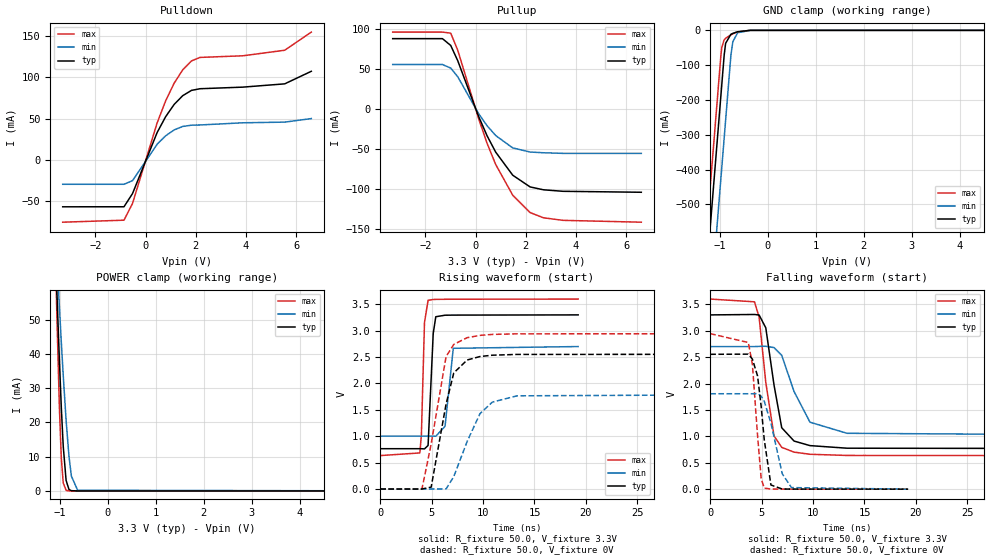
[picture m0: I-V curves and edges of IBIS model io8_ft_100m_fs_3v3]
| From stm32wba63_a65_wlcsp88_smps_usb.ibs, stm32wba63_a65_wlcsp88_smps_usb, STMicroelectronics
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[Model]   io8_ft_100m_fs_3v3
Model_type I/O
Polarity   Non-Inverting
Enable   Active-Low
| CAP_THRESHOLD on pad IOFT is "UDTCAPC" :
| Rising=30.0% of vddiom   Falling=70.0% of vddiom
| C_comp min and max val. don't necessarily correlate with the min and max pvt
| but are the smallest and greatest pad capacitance found.
| var   typ   min   max
C_comp   3.79770pF  3.69235pF  3.85115pF
|C_comp_pullup   2.35214pF  2.17429pF  2.43333pF
|C_comp_pulldown   1.44556pF  1.51806pF  1.41783pF
Vinl = 1.35V
Vinh = 1.8V
Vmeas = 1.65V   | Reference voltage for timing measurements
Cref  = 50.0pF   | Timing specification test load capacitance value
Rref  = 1.0MOhm   | Timing specification test load resistance value
Vref  = 1.815V   | Timing specification test load voltage
[Model Spec]
| TIME_THRESHOLD on pin ZIV11 is "CMOS" :
| Rising=50.0% of vdd   Falling=50.0% of vdd
Vinl 1.29050V 1.08050V 1.37650V
Vinh 1.79850V 1.52050V 1.90250V
| variable   typ   min   max
[Temperature Range] 25.0 140.0 -40.0
| variable   typ   min   max
[Voltage Range] 3.3V 2.7V 3.6V
| variable   typ   min   max
[POWER Clamp Reference] 3.3V 2.7V 3.6V
| variable   typ   min   max
[GND Clamp Reference] 0V 0V 0V
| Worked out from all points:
|   slope of the pulldown table from 0 to 0.495 V, typ, clamps not added: 14 ohm
|   slope of the pullup table from 0 to 0.495 V, typ, clamps not added: 13.8 ohm
|   GND clamp passes 1 mA (typ) near -0.51 V on its own axis
|   POWER clamp passes 1 mA (typ) near -0.83 V on its own axis
|   rising waveform, R_fixture 50.0, V_fixture 3.3V: 20-80 % time 250ps typ, 341ps min, 242ps max; typ from 0.764 V to 3.3 V
|   falling waveform, R_fixture 50.0, V_fixture 3.3V: 20-80 % time 1.12ns typ, 1.99ns min, 1.08ns max; typ from 3.3 V to 0.764 V
|   rising waveform, R_fixture 50.0, V_fixture 0V: 20-80 % time 1.41ns typ, 2.4ns min, 1.46ns max; typ from 0 V to 2.55 V
|   falling waveform, R_fixture 50.0, V_fixture 0V: 20-80 % time 784ps typ, 1.24ns min, 661ps max; typ from 2.55 V to 0 V
[POWER Clamp]
-3.3V     1.123A     753mA      1.645A
-1.09V    69.42mA    75.17mA    67.14mA
-1.08V    65.31mA    72.42mA    61.23mA
-1.06V    57.23mA    66.98mA    49.77mA
-1.01V    38.06mA    53.68mA    24.29mA
-970mV    24.36mA    43.46mA    9.575mA
-930mV    13.06mA    33.74mA    2.352mA
-870mV    3.065mA    20.56mA    165.9uA
-810mV    418.4uA    10.06mA    10.3uA
-760mV    69.41uA    4.321mA    1.009uA
-630mV    611.5nA    197uA      2.727nA
6.6V      0A         0A         0A
[GND Clamp]
-3.3V     -4.134A    -4.372A    -4.018A
-1.59V    -1.227A    -1.465A    -1.111A
-1.25V    -648.9mA   -886.9mA   -533mA
-980mV    -189.9mA   -427.9mA   -74mA
-960mV    -155.9mA   -393.9mA   -48.8mA
-910mV    -70.86mA   -308.9mA   -27.2mA
-880mV    -37.23mA   -257.9mA   -22.76mA
-770mV    -11.28mA   -71.59mA   -12.95mA
-730mV    -8.709mA   -32.74mA   -10.07mA
-630mV    -4.122mA   -6.943mA   -4.354mA
-370mV    -42.68uA   -212.2uA   -13.03uA
6.6V      2.311nA    506.4nA    1.057nA
| variable   typ   min   max
[Pullup Reference] 3.3V 2.7V 3.6V
| variable   typ   min   max
[Pulldown Reference] 0V 0V 0V
[Pullup]
-3.3V     87.39mA    55.15mA    95.56mA
-1.32V    87.39mA    55.15mA    95.56mA
-990mV    78.89mA    50.68mA    94.2mA
-710mV    59.88mA    39.92mA    72.92mA
120mV     -9.566mA   -6.09mA    -12.19mA
460mV     -33.83mA   -21.24mA   -43.26mA
800mV     -54.04mA   -33.36mA   -69.41mA
1.48V     -82.86mA   -48.82mA   -107.8mA
2.17V     -97.42mA   -53.93mA   -129.4mA
2.7V      -101mA     -54.85mA   -135.9mA
3.48V     -102.9mA   -55.62mA   -139.1mA
6.6V      -104.1mA   -55.62mA   -141.4mA
[Pulldown]
-3.3V     -56.7mA    -29.42mA   -75.36mA
-860mV    -56.67mA   -29.42mA   -72.94mA
-520mV    -40.69mA   -25.01mA   -52.64mA
460mV     33.25mA    19.09mA    44.92mA
800mV     52.54mA    29.36mA    71.75mA
1.14V     67.41mA    36.49mA    93.2mA
1.48V     77.97mA    40.67mA    109.3mA
1.83V     84.38mA    42.18mA    120.1mA
2.17V     86.37mA    42.45mA    124.3mA
3.88V     88.31mA    45.1mA     126.3mA
5.54V     92.28mA    45.89mA    133mA
6.6V      107.5mA    50.2mA     155mA
[Ramp]
dV/dt_r 1.53258V/1.41096ns 1.08445V/2.35854ns 1.76673V/1.46232ns
dV/dt_f 1.52157V/1.12301ns 1.019V/1.90102ns 1.77971V/1.07615ns
R_load = 50.0
| Removed startup time: 0s 0s 0s  .
| Removed end time: 19.25ns.
[Rising Waveform]
R_fixture   = 50.0
V_fixture   = 3.3V
V_fixture_min = 2.7V
V_fixture_max = 3.6V
0s        764mV      1.002V     633.8mV
3.85ns    764.1mV    1.002V     683.9mV
4ns       764mV      1.002V     1.032V
4.3ns     759.9mV    1.002V     3.154V
4.65ns    825.9mV    1.002V     3.576V
5.15ns    2.948V     1.002V     3.592V
5.4ns     3.265V     1.001V     3.594V
6.3ns     3.294V     1.188V     3.596V
7.1ns     3.296V     2.667V     3.597V
19.25ns   3.3V       2.7V       3.6V
| Removed startup time: 0s 0s 0s  .
| Removed end time: 59.25ns.
[Falling Waveform]
R_fixture   = 50.0
V_fixture   = 3.3V
V_fixture_min = 2.7V
V_fixture_max = 3.6V
0s        3.3V       2.7V       3.6V
4.3ns     3.308V     2.7V       3.548V
4.75ns    3.298V     2.704V     3.257V
5.4ns     3.055V     2.706V     2.021V
6.2ns     1.973V     2.681V     1.009V
6.95ns    1.163V     2.535V     791.5mV
8.15ns    911.2mV    1.849V     701.3mV
9.7ns     824.8mV    1.268V     660.7mV
13.3ns    775.8mV    1.058V     638.4mV
59.25ns   764mV      1.002V     633.8mV
| Removed startup time: 0s 0s 0s  .
| Removed end time: 59.25ns.
[Rising Waveform]
R_fixture   = 50.0
V_fixture   = 0V
V_fixture_min = 0V
V_fixture_max = 0V
0s        20.8nV     123.7nV    58.33nV
4.05ns    193.8uV    5.146uV    -2.885mV
4.95ns    35.76mV    34.68uV    851.3mV
6.4ns     1.611V     1.837mV    2.511V
7.15ns    2.201V     236.1mV    2.741V
8.45ns    2.445V     901.5mV    2.868V
9.7ns     2.511V     1.429V     2.912V
10.9ns    2.536V     1.647V     2.93V
13.3ns    2.551V     1.766V     2.941V
59.25ns   2.554V     1.807V     2.945V
| Removed startup time: 0s 0s 0s  .
| Removed end time: 19.25ns.
[Falling Waveform]
R_fixture   = 50.0
V_fixture   = 0V
V_fixture_min = 0V
V_fixture_max = 0V
0s        2.554V     1.807V     2.945V
3.7ns     2.557V     1.807V     2.777V
4.1ns     2.462V     1.807V     2.36V
4.6ns     2.143V     1.81V      1.009V
4.95ns    1.567V     1.762V     203.2mV
5.25ns    935.6mV    1.665V     19.13mV
5.9ns     79.06mV    1.25V      2.647mV
7ns       2.54mV     292.4mV    1.373mV
7.9ns     1.543mV    29.8mV     1.011mV
19.25ns   28.21uV    81.63uV    25.08uV
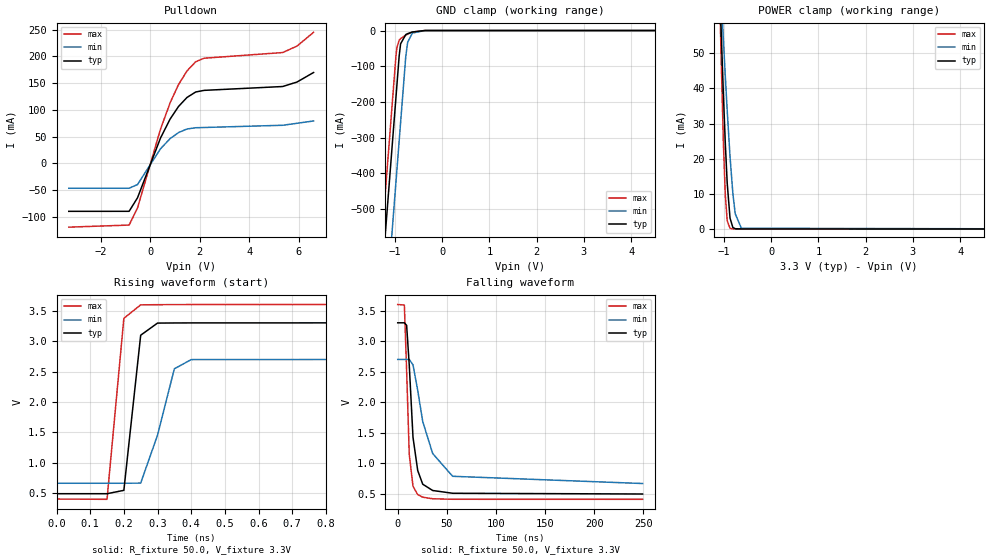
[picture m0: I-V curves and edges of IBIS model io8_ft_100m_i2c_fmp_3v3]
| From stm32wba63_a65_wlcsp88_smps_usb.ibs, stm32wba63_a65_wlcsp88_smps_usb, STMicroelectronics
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[Model]   io8_ft_100m_i2c_fmp_3v3
Model_type I/O_open_drain
Polarity   Non-Inverting
Enable   Active-Low
| CAP_THRESHOLD on pad IOFT is "UDTCAPC" :
| Rising=30.0% of vddiom   Falling=70.0% of vddiom
| C_comp min and max val. don't necessarily correlate with the min and max pvt
| but are the smallest and greatest pad capacitance found.
| var   typ   min   max
C_comp   3.81294pF  3.70667pF  3.87011pF
|C_comp_pulldown   3.81294pF  3.70667pF  3.87011pF
Vinl = 1.35V
Vinh = 1.8V
Vmeas = 1.65V   | Reference voltage for timing measurements
Cref  = 50.0pF   | Timing specification test load capacitance value
Rref  = 1.0MOhm   | Timing specification test load resistance value
Vref  = 1.815V   | Timing specification test load voltage
[Model Spec]
| TIME_THRESHOLD on pin ZII2CV11 is "CMOS" :
| Rising=50.0% of vdd   Falling=50.0% of vdd
Vinl 1.29050V 1.08050V 1.37650V
Vinh 1.79850V 1.52050V 1.90250V
| variable   typ   min   max
[Temperature Range] 25.0 140.0 -40.0
| variable   typ   min   max
[Voltage Range] 3.3V 2.7V 3.6V
| variable   typ   min   max
[POWER Clamp Reference] 3.3V 2.7V 3.6V
| variable   typ   min   max
[GND Clamp Reference] 0V 0V 0V
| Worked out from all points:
|   slope of the pulldown table from 0 to 0.495 V, typ, clamps not added: 8.84 ohm
|   GND clamp passes 1 mA (typ) near -0.51 V on its own axis
|   POWER clamp passes 1 mA (typ) near -0.83 V on its own axis
|   rising waveform, R_fixture 50.0, V_fixture 3.3V: 20-80 % time 33.1ps typ, 62.8ps min, 32.2ps max; typ from 0.496 V to 3.3 V
|   falling waveform, R_fixture 50.0, V_fixture 3.3V: 20-80 % time 7.18ns typ, 18.7ns min, 3.98ns max; typ from 3.3 V to 0.496 V
[POWER Clamp]
-3.3V     1.123A     753mA      1.645A
-1.09V    69.42mA    75.17mA    67.14mA
-1.08V    65.31mA    72.42mA    61.23mA
-1.06V    57.23mA    66.98mA    49.77mA
-1.01V    38.06mA    53.68mA    24.29mA
-970mV    24.36mA    43.46mA    9.575mA
-930mV    13.06mA    33.74mA    2.352mA
-870mV    3.065mA    20.56mA    165.9uA
-810mV    418.4uA    10.06mA    10.3uA
-760mV    69.41uA    4.321mA    1.009uA
-630mV    611.5nA    197uA      2.727nA
6.6V      0A         0A         0A
[GND Clamp]
-3.3V     -4.134A    -4.372A    -4.018A
-1.59V    -1.227A    -1.465A    -1.111A
-1.25V    -648.9mA   -886.9mA   -533mA
-980mV    -189.9mA   -427.9mA   -74mA
-960mV    -155.9mA   -393.9mA   -48.8mA
-910mV    -70.86mA   -308.9mA   -27.2mA
-880mV    -37.23mA   -257.9mA   -22.76mA
-770mV    -11.28mA   -71.59mA   -12.95mA
-730mV    -8.709mA   -32.74mA   -10.07mA
-630mV    -4.122mA   -6.943mA   -4.354mA
-370mV    -42.68uA   -212.2uA   -13.03uA
6.6V      2.311nA    506.4nA    1.057nA
| variable   typ   min   max
[Pullup Reference] 3.3V 2.7V 3.6V
| variable   typ   min   max
[Pulldown Reference] 0V 0V 0V
[Pulldown]
-3.3V     -89.63mA   -46.48mA   -119.2mA
-860mV    -89.58mA   -46.48mA   -115.3mA
-520mV    -64.32mA   -39.52mA   -83.23mA
410mV     47.47mA    27.34mA    64.07mA
800mV     83.04mA    46.39mA    113.5mA
1.14V     106.5mA    57.66mA    147.4mA
1.48V     123.2mA    64.27mA    172.8mA
1.83V     133.4mA    66.65mA    189.9mA
2.17V     136.5mA    67.08mA    196.6mA
5.35V     143.7mA    71.26mA    207.2mA
5.93V     152.1mA    74.98mA    219.3mA
6.6V      169.9mA    79.29mA    245mA
[Ramp]
dV/dt_r 1.6826V/583.11244ps 1.21966V/1.13387ns 1.91502V/366.99636ps
dV/dt_f 1.68262V/7.00601ns 1.21963V/18.44848ns 1.91504V/3.82343ns
R_load = 50.0
| Removed startup time: 0s 0s 0s  .
| Removed end time: 1.7ns.
[Rising Waveform]
R_fixture   = 50.0
V_fixture   = 3.3V
V_fixture_min = 2.7V
V_fixture_max = 3.6V
0s        495.6mV    667.2mV    408.3mV
150ps     495.6mV    667.2mV    403.4mV
200ps     551.1mV    667.2mV    3.373V
250ps     3.096V     669.6mV    3.594V
300ps     3.295V     1.456V     3.597V
350ps     3.297V     2.545V     3.598V
400ps     3.298V     2.696V     3.599V
1.7ns     3.3V       2.7V       3.6V
| Removed startup time: 0s 0s 0s  .
| Removed end time: 249.25ns.
[Falling Waveform]
R_fixture   = 50.0
V_fixture   = 3.3V
V_fixture_min = 2.7V
V_fixture_max = 3.6V
0s        3.3V       2.7V       3.6V
6.75ns    3.3V       2.7V       3.591V
9.05ns    3.259V     2.7V       2.524V
11.75ns   2.606V     2.7V       1.141V
15.55ns   1.425V     2.612V     622.8mV
20.35ns   880.1mV    2.194V     485mV
25.45ns   656.2mV    1.683V     443.2mV
35.6ns    553mV      1.158V     417.6mV
55.95ns   507.6mV    785.6mV    409.3mV
249.3ns   495.6mV    667.3mV    408.3mV
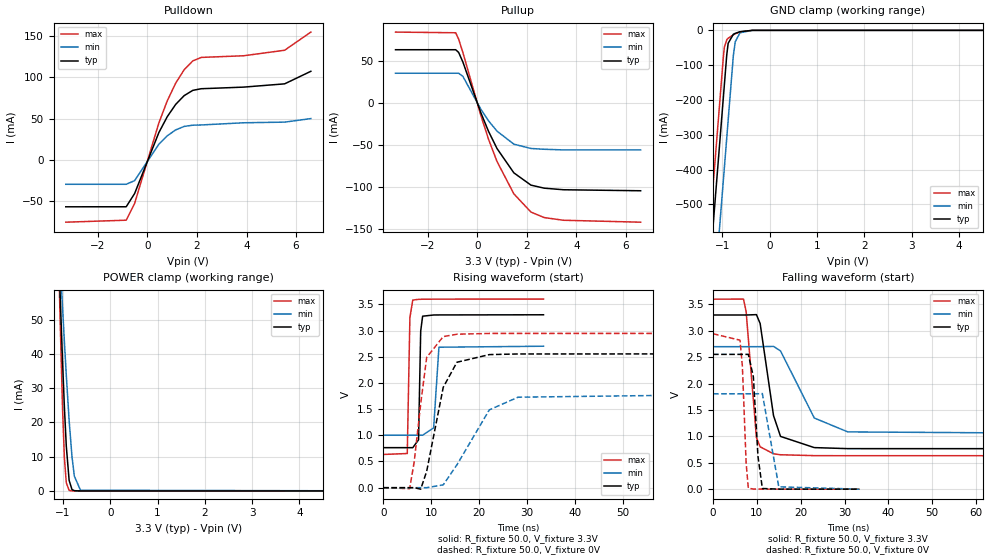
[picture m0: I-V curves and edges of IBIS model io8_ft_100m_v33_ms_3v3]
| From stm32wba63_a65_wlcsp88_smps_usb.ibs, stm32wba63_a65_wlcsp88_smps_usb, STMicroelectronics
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[Model]   io8_ft_100m_v33_ms_3v3
Model_type I/O
Polarity   Non-Inverting
Enable   Active-Low
| CAP_THRESHOLD on pad IOFT is "UDTCAPC" :
| Rising=30.0% of vddiom   Falling=70.0% of vddiom
| C_comp min and max val. don't necessarily correlate with the min and max pvt
| but are the smallest and greatest pad capacitance found.
| var   typ   min   max
C_comp   3.88674pF  3.77801pF  3.94187pF
|C_comp_pullup   2.41867pF  2.25965pF  2.53637pF
|C_comp_pulldown   1.46806pF  1.51835pF  1.40550pF
Vinl = 1.35V
Vinh = 1.8V
Vmeas = 1.65V   | Reference voltage for timing measurements
Cref  = 50.0pF   | Timing specification test load capacitance value
Rref  = 1.0MOhm   | Timing specification test load resistance value
Vref  = 1.815V   | Timing specification test load voltage
[Model Spec]
| TIME_THRESHOLD on pin ZIV33M is "CMOS" :
| Rising=50.0% of vddiom   Falling=50.0% of vddiom
Vinl 1.28450V 1.07450V 1.37050V
Vinh 1.79550V 1.51850V 1.89950V
| variable   typ   min   max
[Temperature Range] 25.0 140.0 -40.0
| variable   typ   min   max
[Voltage Range] 3.3V 2.7V 3.6V
| variable   typ   min   max
[POWER Clamp Reference] 3.3V 2.7V 3.6V
| variable   typ   min   max
[GND Clamp Reference] 0V 0V 0V
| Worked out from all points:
|   slope of the pulldown table from 0 to 0.495 V, typ, clamps not added: 14 ohm
|   slope of the pullup table from 0 to 0.495 V, typ, clamps not added: 13.8 ohm
|   GND clamp passes 1 mA (typ) near -0.51 V on its own axis
|   POWER clamp passes 1 mA (typ) near -0.83 V on its own axis
|   rising waveform, R_fixture 50.0, V_fixture 3.3V: 20-80 % time 264ps typ, 359ps min, 247ps max; typ from 0.764 V to 3.3 V
|   falling waveform, R_fixture 50.0, V_fixture 3.3V: 20-80 % time 2.93ns typ, 6.08ns min, 1.71ns max; typ from 3.3 V to 0.764 V
|   rising waveform, R_fixture 50.0, V_fixture 0V: 20-80 % time 3.4ns typ, 6.88ns min, 2.22ns max; typ from 0 V to 2.55 V
|   falling waveform, R_fixture 50.0, V_fixture 0V: 20-80 % time 1.08ns typ, 1.66ns min, 818ps max; typ from 2.55 V to 0 V
[POWER Clamp]
-3.3V     1.123A     753mA      1.645A
-1.09V    69.42mA    75.17mA    67.14mA
-1.08V    65.31mA    72.42mA    61.23mA
-1.06V    57.23mA    66.98mA    49.77mA
-1.01V    38.06mA    53.68mA    24.29mA
-970mV    24.36mA    43.46mA    9.575mA
-930mV    13.06mA    33.74mA    2.352mA
-870mV    3.065mA    20.56mA    165.9uA
-810mV    418.4uA    10.06mA    10.3uA
-760mV    69.41uA    4.321mA    1.009uA
-630mV    611.5nA    197uA      2.727nA
6.6V      0A         0A         0A
[GND Clamp]
-3.3V     -4.134A    -4.372A    -4.018A
-1.59V    -1.227A    -1.465A    -1.111A
-1.25V    -648.9mA   -886.9mA   -533mA
-980mV    -189.9mA   -427.9mA   -74mA
-960mV    -155.9mA   -393.9mA   -48.8mA
-910mV    -70.86mA   -308.9mA   -27.2mA
-880mV    -37.23mA   -257.9mA   -22.76mA
-770mV    -11.28mA   -71.59mA   -12.95mA
-730mV    -8.709mA   -32.74mA   -10.07mA
-630mV    -4.122mA   -6.943mA   -4.354mA
-370mV    -42.68uA   -212.2uA   -13.03uA
6.6V      2.31nA     506.4nA    1.057nA
| variable   typ   min   max
[Pullup Reference] 3.3V 2.7V 3.6V
| variable   typ   min   max
[Pulldown Reference] 0V 0V 0V
[Pullup]
-3.3V     63.27mA    35.35mA    84.19mA
-870mV    63.27mA    35.35mA    83.39mA
-750mV    60.02mA    35.35mA    75.73mA
-580mV    48.71mA    31.68mA    59.96mA
140mV     -11.11mA   -7.067mA   -14.16mA
460mV     -33.83mA   -21.24mA   -43.26mA
800mV     -54.04mA   -33.36mA   -69.41mA
1.48V     -82.86mA   -48.82mA   -107.8mA
2.17V     -97.42mA   -53.93mA   -129.4mA
2.7V      -101mA     -54.85mA   -135.9mA
3.48V     -102.9mA   -55.62mA   -139.1mA
6.6V      -104.1mA   -55.62mA   -141.4mA
[Pulldown]
-3.3V     -56.7mA    -29.42mA   -75.36mA
-860mV    -56.67mA   -29.42mA   -72.94mA
-520mV    -40.69mA   -25.01mA   -52.64mA
460mV     33.25mA    19.09mA    44.92mA
800mV     52.54mA    29.36mA    71.75mA
1.14V     67.41mA    36.49mA    93.2mA
1.48V     77.97mA    40.67mA    109.3mA
1.83V     84.38mA    42.18mA    120.1mA
2.17V     86.37mA    42.45mA    124.3mA
3.88V     88.31mA    45.11mA    126.3mA
5.54V     92.28mA    45.89mA    133mA
6.6V      107.5mA    50.2mA     155mA
[Ramp]
dV/dt_r 1.53258V/3.33851ns 1.08444V/6.80774ns 1.76673V/2.21529ns
dV/dt_f 1.52157V/2.69177ns 1.019V/5.93039ns 1.77971V/1.7014ns
R_load = 50.0
| Removed startup time: 0s 0s 0s  .
| Removed end time: 33.4ns.
[Rising Waveform]
R_fixture   = 50.0
V_fixture   = 3.3V
V_fixture_min = 2.7V
V_fixture_max = 3.6V
0s        764mV      1.002V     633.8mV
5ns       764.1mV    1.002V     652.3mV
5.55ns    764.1mV    1.002V     3.248V
6.15ns    764.1mV    1.002V     3.581V
7.35ns    913.4mV    1.002V     3.595V
7.8ns     2.989V     1.002V     3.596V
8.2ns     3.273V     1.002V     3.597V
10.5ns    3.296V     1.142V     3.598V
11.6ns    3.297V     2.681V     3.599V
33.4ns    3.3V       2.7V       3.6V
| Removed startup time: 0s 0s 0s  .
| Removed end time: 188.4ns.
[Falling Waveform]
R_fixture   = 50.0
V_fixture   = 3.3V
V_fixture_min = 2.7V
V_fixture_max = 3.6V
0s        3.3V       2.7V       3.6V
6.95ns    3.3V       2.7V       3.602V
7.55ns    3.3V       2.7V       3.365V
9.9ns     3.307V     2.7V       976.7mV
10.75ns   3.138V     2.7V       803mV
13.8ns    1.393V     2.705V     669.9mV
15.4ns    999.5mV    2.619V     652mV
23.1ns    787.5mV    1.348V     635.1mV
30.75ns   768.1mV    1.085V     634mV
188.4ns   764mV      1.002V     633.8mV
| Removed startup time: 0s 0s 0s  .
| Removed end time: 98.35ns.
[Rising Waveform]
R_fixture   = 50.0
V_fixture   = 0V
V_fixture_min = 0V
V_fixture_max = 0V
0s        20.88nV    123.8nV    58.45nV
5.5ns     2.011uV    120.1nV    -18.83mV
6.45ns    78.41uV    127.1nV    496.8mV
7.8ns     -28.33mV   2.567uV    1.599V
9.05ns    313.5mV    19.61uV    2.488V
12.5ns    1.916V     54.09mV    2.884V
15.35ns   2.394V     435.4mV    2.929V
22.1ns    2.54V      1.485V     2.944V
28.1ns    2.552V     1.727V     2.944V
98.35ns   2.554V     1.807V     2.945V
| Removed startup time: 0s 0s 0s  .
| Removed end time: 33.4ns.
[Falling Waveform]
R_fixture   = 50.0
V_fixture   = 0V
V_fixture_min = 0V
V_fixture_max = 0V
0s        2.554V     1.807V     2.945V
6.15ns    2.554V     1.807V     2.823V
6.7ns     2.554V     1.807V     2.324V
7.55ns    2.554V     1.807V     496mV
8.05ns    2.554V     1.807V     18.68mV
9.2ns     2.13V      1.807V     1.981mV
10.25ns   626.4mV    1.807V     1.228mV
11.25ns   12.65mV    1.812V     921.3uV
15ns      971.6uV    44.15mV    423.8uV
33.4ns    28.91uV    219uV      3.058uV
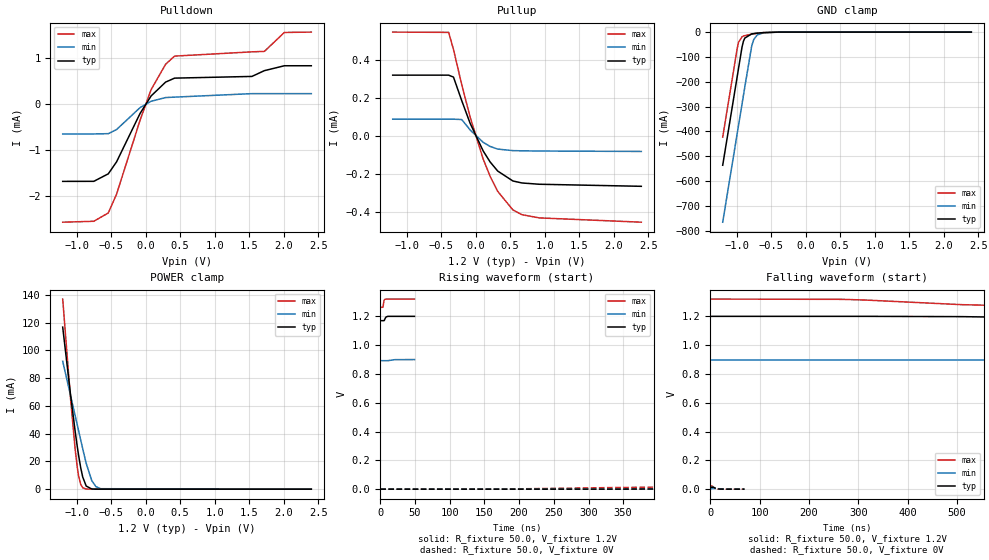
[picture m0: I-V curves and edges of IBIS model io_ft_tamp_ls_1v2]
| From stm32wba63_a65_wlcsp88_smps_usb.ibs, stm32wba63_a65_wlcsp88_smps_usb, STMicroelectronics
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[Model]   io_ft_tamp_ls_1v2
Model_type I/O
Polarity   Non-Inverting
Enable   Active-Low
| CAP_THRESHOLD on pad IOFT is "UDTCAPC" :
| Rising=30.0% of vddios   Falling=70.0% of vddios
| C_comp min and max val. don't necessarily correlate with the min and max pvt
| but are the smallest and greatest pad capacitance found.
| var   typ   min   max
C_comp   2.36572pF  2.32096pF  2.42359pF
|C_comp_pullup   1.37557pF  1.27769pF  1.46043pF
|C_comp_pulldown   990.15399fF  1.04327pF  963.15792fF
Vinl = 450.0mV
Vinh = 660.0mV
Vmeas = 600.0mV   | Reference voltage for timing measurements
Cref  = 50.0pF   | Timing specification test load capacitance value
Rref  = 1.0MOhm   | Timing specification test load resistance value
Vref  = 660.0mV   | Timing specification test load voltage
[Model Spec]
| TIME_THRESHOLD on pin ZIV11 is "CMOS" :
| Rising=50.0% of vdd   Falling=50.0% of vdd
Vinl 441.50000mV 335.50000mV 487.50000mV
Vinh 755.50000mV 552.50000mV 839.50000mV
| variable   typ   min   max
[Temperature Range] 25.0 140.0 -40.0
| variable   typ   min   max
[Voltage Range] 1.2V 900.0mV 1.32V
| variable   typ   min   max
[POWER Clamp Reference] 1.2V 900.0mV 1.32V
| variable   typ   min   max
[GND Clamp Reference] 0V 0V 0V
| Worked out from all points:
|   slope of the pulldown table from 0 to 0.18 V, typ, clamps not added: 522 ohm
|   slope of the pullup table from 0 to 0.18 V, typ, clamps not added: 1.49 kohm
|   GND clamp passes 1 mA (typ) near -0.54 V on its own axis
|   POWER clamp passes 1 mA (typ) near -0.83 V on its own axis
[POWER Clamp]
-1.2V     116.7mA    92.13mA    136.9mA
-1.09V    69.42mA    68.21mA    67.14mA
-1.02V    41.75mA    52.99mA    28.91mA
-990mV    30.98mA    46.47mA    16.09mA
-970mV    24.36mA    42.12mA    9.575mA
-940mV    15.59mA    35.6mA     3.485mA
-910mV    8.693mA    29.07mA    1.01mA
-860mV    2.259mA    18.59mA    104.6uA
-780mV    143.1uA    6.246mA    2.554uA
-720mV    16.22uA    1.846mA    157.1nA
-650mV    1.266uA    330.3uA    6.104nA
2.4V      0A         0A         0A
[GND Clamp]
-1.2V     -535.9mA   -765.1mA   -422.7mA
-990mV    -178.9mA   -408.1mA   -65.72mA
-970mV    -144.9mA   -374.1mA   -40.58mA
-920mV    -59.91mA   -289.1mA   -18.78mA
-900mV    -37.04mA   -255.1mA   -15.98mA
-880mV    -24.11mA   -221.1mA   -14.15mA
-780mV    -7.189mA   -55.54mA   -8.417mA
-750mV    -5.884mA   -29.71mA   -7.031mA
-700mV    -4.228mA   -11.41mA   -4.967mA
-610mV    -2.056mA   -3.105mA   -2.146mA
-390mV    -47.28uA   -188.8uA   -17.26uA
2.4V      740.6pA    197.9nA    245.1pA
| variable   typ   min   max
[Pullup Reference] 1.2V 900.0mV 1.32V
| variable   typ   min   max
[Pulldown Reference] 0V 0V 0V
[Pullup]
-1.2V     321.3uA    88.9uA     548.6uA
-390mV    321.3uA    88.9uA     547.1uA
-320mV    311uA      88.9uA     456.9uA
-200mV    186.3uA    86.88uA    270.6uA
-80mV     68.07uA    32.43uA    101.5uA
110mV     -78.95uA   -33.53uA   -121.5uA
210mV     -136.6uA   -54.89uA   -212.5uA
320mV     -184.8uA   -68.93uA   -292uA
540mV     -237.3uA   -77.06uA   -389.8uA
670mV     -247.8uA   -78.09uA   -415.1uA
920mV     -254.6uA   -79.22uA   -432.2uA
2.4V      -265.5uA   -81.48uA   -454.9uA
[Pulldown]
-1.2V     -1.691mA   -654.4uA   -2.583mA
-750mV    -1.69mA    -654.4uA   -2.563mA
-540mV    -1.526mA   -648uA     -2.381mA
-420mV    -1.264mA   -558.1uA   -1.971mA
-80mV     -206.7uA   -79.07uA   -354.6uA
80mV      176uA      59.8uA     314uA
290mV     478.8uA    141uA      868.7uA
420mV     565.7uA    150.3uA    1.047mA
1.54V     603uA      226.7uA    1.14mA
1.72V     729uA      226.7uA    1.15mA
2.01V     836.2uA    226.7uA    1.564mA
2.4V      836.2uA    226.7uA    1.572mA
[Ramp]
dV/dt_r 7.74089mV/409.16727ns 2.36364mV/1.05135us 13.24767mV/226.86306ns
dV/dt_f 17.9434mV/387.10712ns 4.52375mV/1.02758us 34.19464mV/229.19862ns
R_load = 50.0
| Removed startup time: 0s 0s 0s  .
| Removed end time: 49.25ns.
[Rising Waveform]
R_fixture   = 50.0
V_fixture   = 1.2V
V_fixture_min = 900.0mV
V_fixture_max = 1.32V
0s        1.17V      892.4mV    1.263V
3.85ns    1.17V      892.4mV    1.263V
5.05ns    1.17V      892.4mV    1.3V
5.45ns    1.17V      892.4mV    1.31V
6.15ns    1.175V     892.4mV    1.317V
6.95ns    1.185V     892.4mV    1.319V
8.35ns    1.196V     892.4mV    1.32V
11.05ns   1.2V       892.4mV    1.32V
21.15ns   1.2V       899.3mV    1.32V
49.25ns   1.2V       900mV      1.32V
| Removed startup time: 0s 0s 0s  .
| Removed end time: 4.9989us.
[Falling Waveform]
R_fixture   = 50.0
V_fixture   = 1.2V
V_fixture_min = 900.0mV
V_fixture_max = 1.32V
0s        1.2V       900mV      1.32V
268.9ns   1.2V       900mV      1.318V
315.4ns   1.2V       900mV      1.313V
510.1ns   1.198V     900mV      1.281V
666ns     1.19V      900mV      1.269V
842.6ns   1.181V     900mV      1.264V
1.122us   1.173V     899.9mV    1.263V
1.53us    1.171V     898.8mV    1.263V
2.857us   1.17V      893.5mV    1.263V
4.999us   1.17V      892.5mV    1.263V
| Removed startup time: 0s 0s 0s  .
| Removed end time: 4.9989us.
[Rising Waveform]
R_fixture   = 50.0
V_fixture   = 0V
V_fixture_min = 0V
V_fixture_max = 0V
0s        10.49nV    318.6nV    9.881nV
171ns     -2.032uV   -719.7nV   482.6uV
322.1ns   175.3uV    -449.9nV   10.27mV
449.4ns   2.251mV    125.3nV    17.03mV
584.3ns   5.415mV    2.338uV    20.3mV
714.4ns   8.086mV    8.216uV    21.45mV
1.02us    11.47mV    83.73uV    22.01mV
1.429us   12.65mV    805.2uV    22.07mV
2.755us   12.9mV     3.449mV    22.08mV
4.999us   12.9mV     3.94mV     22.08mV
| Removed startup time: 0s 0s 0s  .
| Removed end time: 69.25ns.
[Falling Waveform]
R_fixture   = 50.0
V_fixture   = 0V
V_fixture_min = 0V
V_fixture_max = 0V
0s        12.91mV    3.958mV    22.08mV
3.95ns    12.9mV     3.958mV    22.13mV
5.95ns    12.88mV    3.957mV    15.52mV
9.8ns     8.016mV    3.963mV    5.097mV
11.95ns   5.669mV    3.944mV    1.652mV
14.5ns    3.331mV    3.487mV    335.6uV
18.4ns    882.3uV    2.825mV    139uV
22.65ns   192.9uV    2.166mV    65.4uV
41ns      18.69uV    289.4uV    2.611uV
69.25ns   923.4nV    22.15uV    1.133uV
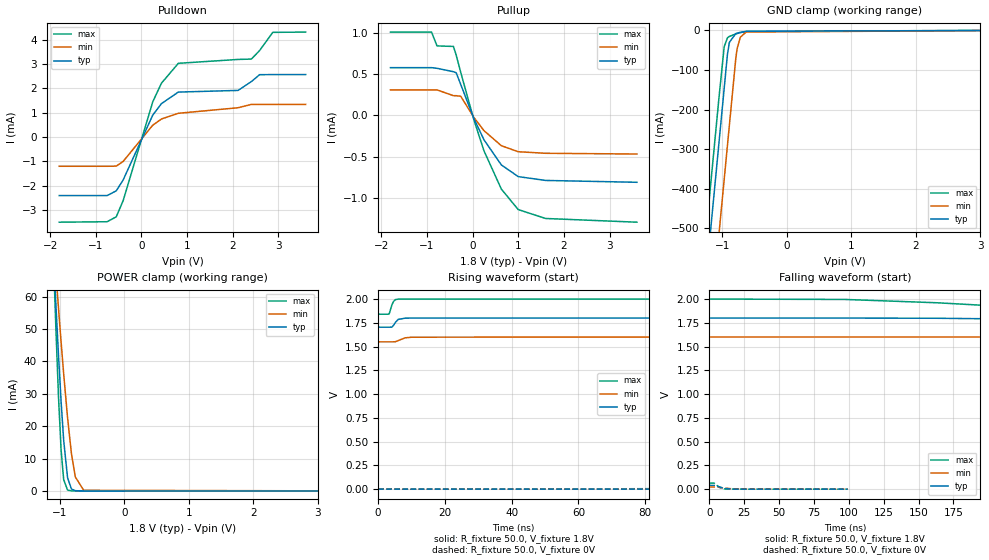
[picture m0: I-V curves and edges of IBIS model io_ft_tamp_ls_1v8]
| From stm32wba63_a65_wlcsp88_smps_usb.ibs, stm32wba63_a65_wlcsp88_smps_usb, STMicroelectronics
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[Model]   io_ft_tamp_ls_1v8
Model_type I/O
Polarity   Non-Inverting
Enable   Active-Low
| CAP_THRESHOLD on pad IOFT is "UDTCAPC" :
| Rising=30.0% of vddios   Falling=70.0% of vddios
| C_comp min and max val. don't necessarily correlate with the min and max pvt
| but are the smallest and greatest pad capacitance found.
| var   typ   min   max
C_comp   2.67029pF  2.66323pF  2.74961pF
|C_comp_pullup   1.57191pF  1.51367pF  1.65630pF
|C_comp_pulldown   1.09837pF  1.14956pF  1.09331pF
Vinl = 800.0mV
Vinh = 1.0V
Vmeas = 900.0mV   | Reference voltage for timing measurements
Cref  = 50.0pF   | Timing specification test load capacitance value
Rref  = 1.0MOhm   | Timing specification test load resistance value
Vref  = 990.0mV   | Timing specification test load voltage
[Model Spec]
| TIME_THRESHOLD on pin ZIV11 is "CMOS" :
| Rising=50.0% of vdd   Falling=50.0% of vdd
Vinl 702.50000mV 626.50000mV 788.50000mV
Vinh 1.09050V 959.50000mV 1.19650V
| variable   typ   min   max
[Temperature Range] 25.0 140.0 -40.0
| variable   typ   min   max
[Voltage Range] 1.8V 1.6V 2.0V
| variable   typ   min   max
[POWER Clamp Reference] 1.8V 1.6V 2.0V
| variable   typ   min   max
[GND Clamp Reference] 0V 0V 0V
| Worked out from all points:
|   slope of the pulldown table from 0 to 0.27 V, typ, clamps not added: 284 ohm
|   slope of the pullup table from 0 to 0.27 V, typ, clamps not added: 860 ohm
|   GND clamp passes 1 mA (typ) near -0.54 V on its own axis
|   POWER clamp passes 1 mA (typ) near -0.83 V on its own axis
|   rising waveform, R_fixture 50.0, V_fixture 1.8V: 20-80 % time 1.22ns typ, NA min, 931ps max; typ from 1.7 V to 1.8 V
|   falling waveform, R_fixture 50.0, V_fixture 1.8V: 20-80 % time 214ns typ, NA min, 141ns max; typ from 1.8 V to 1.7 V
[POWER Clamp]
-1.8V     396.4mA    285.5mA    556.9mA
-1.09V    69.42mA    75.17mA    67.14mA
-1.08V    65.31mA    72.42mA    61.23mA
-1.06V    57.23mA    66.98mA    49.77mA
-1.02V    41.75mA    56.3mA     28.91mA
-980mV    27.6mA     45.97mA    12.6mA
-940mV    15.59mA    36.11mA    3.485mA
-880mV    4.091mA    22.61mA    262.5uA
-820mV    594.6uA    11.56mA    16.39uA
-760mV    69.41uA    4.321mA    1.008uA
-630mV    610.8nA    197uA      2.464nA
3.6V      0A         0A         0A
[GND Clamp]
-1.8V     -1.557A    -1.787A    -1.443A
-1.33V    -757.8mA   -987.8mA   -644.3mA
-1.24V    -604.8mA   -834.8mA   -491.3mA
-1.05V    -281.8mA   -511.8mA   -168.3mA
-970mV    -145.8mA   -375.8mA   -41.09mA
-920mV    -60.82mA   -290.8mA   -19.19mA
-890mV    -30.35mA   -239.8mA   -15.35mA
-790mV    -8.023mA   -70.37mA   -9.131mA
-770mV    -6.967mA   -46.42mA   -8.145mA
-720mV    -5.017mA   -17.37mA   -5.895mA
-630mV    -2.538mA   -4.268mA   -2.717mA
3.6V      1.094nA    260.9nA    370.3pA
| variable   typ   min   max
[Pullup Reference] 1.8V 1.6V 2.0V
| variable   typ   min   max
[Pulldown Reference] 0V 0V 0V
[Pullup]
-1.8V     581uA      310.8uA    1.013mA
-900mV    581uA      310.8uA    1.013mA
-780mV    573uA      310.8uA    845uA
-420mV    531.8uA    240.6uA    838.7uA
-360mV    519.6uA    240.6uA    734.4uA
-260mV    377.1uA    233.1uA    523.7uA
30mV      -39.57uA   -24.87uA   -57.04uA
250mV     -295.5uA   -184.4uA   -429.9uA
630mV     -600.6uA   -367.2uA   -894uA
1V        -742.5uA   -440.3uA   -1.143mA
1.6V      -788.9uA   -459.1uA   -1.251mA
3.6V      -811.3uA   -468uA     -1.296mA
[Pulldown]
-1.8V     -2.401mA   -1.198mA   -3.493mA
-750mV    -2.4mA     -1.198mA   -3.474mA
-550mV    -2.207mA   -1.193mA   -3.271mA
-400mV    -1.763mA   -1.002mA   -2.612mA
250mV     901.5uA    487.8uA    1.448mA
440mV     1.372mA    740.4uA    2.21mA
810mV     1.846mA    975.3uA    3.026mA
2.12V     1.914mA    1.203mA    3.185mA
2.41V     2.276mA    1.339mA    3.199mA
2.59V     2.559mA    1.339mA    3.547mA
2.88V     2.564mA    1.339mA    4.296mA
3.6V      2.564mA    1.339mA    4.307mA
[Ramp]
dV/dt_r 23.80185mV/239.86131ns 13.72602mV/467.94544ns 38.015mV/140.17815ns
dV/dt_f 57.33007mV/213.40371ns 29.79554mV/373.12078ns 95.55754mV/139.49218ns
R_load = 50.0
| Removed startup time: 0s 0s 0s  .
| Removed end time: 99.2ns.
[Rising Waveform]
R_fixture   = 50.0
V_fixture   = 1.8V
V_fixture_min = 1.6V
V_fixture_max = 2.0V
0s        1.704V     1.55V      1.841V
3.2ns     1.704V     1.55V      1.841V
3.4ns     1.704V     1.55V      1.854V
4.15ns    1.705V     1.55V      1.941V
4.6ns     1.724V     1.55V      1.974V
5.15ns    1.753V     1.551V     1.994V
6ns       1.786V     1.563V     1.999V
8.1ns     1.799V     1.592V     2V
10.15ns   1.8V       1.599V     2V
99.2ns    1.8V       1.6V       2V
| Removed startup time: 0s 0s 0s  .
| Removed end time: 1.999us.
[Falling Waveform]
R_fixture   = 50.0
V_fixture   = 1.8V
V_fixture_min = 1.6V
V_fixture_max = 2.0V
0s        1.8V       1.6V       2V
97.25ns   1.8V       1.6V       1.996V
163.3ns   1.798V     1.6V       1.961V
236.3ns   1.787V     1.6V       1.902V
266.5ns   1.779V     1.599V     1.884V
323.8ns   1.76V      1.597V     1.862V
408ns     1.736V     1.593V     1.848V
602ns     1.711V     1.575V     1.841V
935.5ns   1.705V     1.556V     1.841V
1.999us   1.704V     1.55V      1.841V
| Removed startup time: 0s 0s 0s  .
| Removed end time: 1.999us.
[Rising Waveform]
R_fixture   = 50.0
V_fixture   = 0V
V_fixture_min = 0V
V_fixture_max = 0V
0s        14.23nV    329.4nV    13.51nV
48ns      -14.01uV   -6.167uV   257.4uV
81.5ns    87.28uV    -3.874uV   5.35mV
197.3ns   6.914mV    248uV      39.11mV
246.3ns   12.36mV    691.1uV    49.71mV
367.3ns   25.92mV    3.52mV     60.48mV
489.5ns   33.82mV    7.633mV    62.79mV
693.5ns   38.4mV     14.4mV     63.3mV
1.143us   39.62mV    21.31mV    63.35mV
1.999us   39.67mV    22.88mV    63.36mV
| Removed startup time: 0s 0s 0s  .
| Removed end time: 99.2ns.
[Falling Waveform]
R_fixture   = 50.0
V_fixture   = 0V
V_fixture_min = 0V
V_fixture_max = 0V
0s        39.68mV    22.94mV    63.36mV
3.5ns     39.67mV    22.94mV    63.25mV
4.55ns    39.33mV    22.95mV    50.45mV
6.15ns    29.99mV    21.19mV    30.9mV
7.45ns    22.8mV     18.41mV    17.87mV
10.15ns   10.36mV    13.07mV    4.682mV
11.7ns    6.44mV     10.31mV    729.5uV
16.2ns    366.5uV    4.239mV    134.9uV
24.3ns    57.1uV     243uV      12.08uV
99.2ns    2.596uV    1.43uV     7.333uV
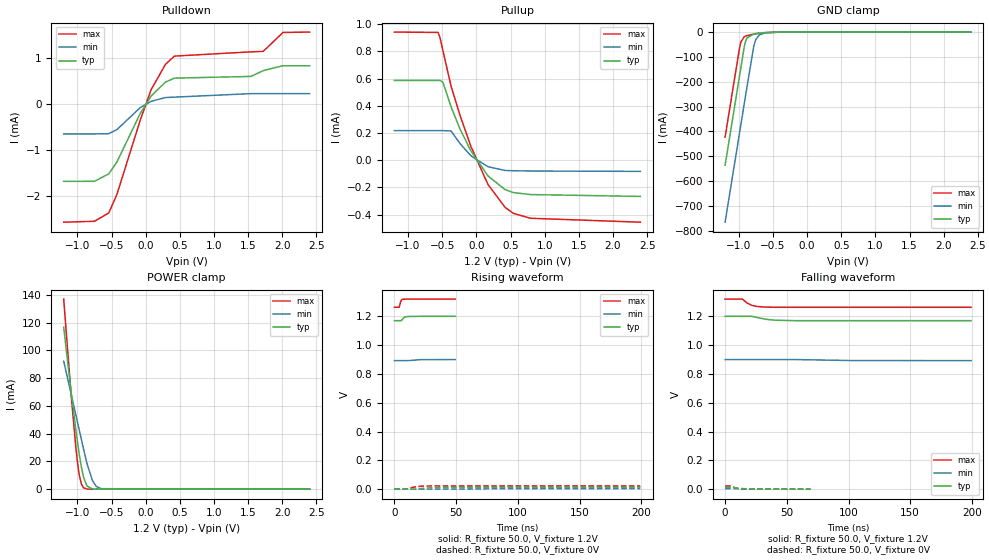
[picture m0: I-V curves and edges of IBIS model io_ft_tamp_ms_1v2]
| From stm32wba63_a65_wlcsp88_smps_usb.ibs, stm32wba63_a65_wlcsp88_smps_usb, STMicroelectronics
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[Model]   io_ft_tamp_ms_1v2
Model_type I/O
Polarity   Non-Inverting
Enable   Active-Low
| CAP_THRESHOLD on pad IOFT is "UDTCAPC" :
| Rising=30.0% of vddios   Falling=70.0% of vddios
| C_comp min and max val. don't necessarily correlate with the min and max pvt
| but are the smallest and greatest pad capacitance found.
| var   typ   min   max
C_comp   2.32868pF  2.27595pF  2.39710pF
|C_comp_pullup   1.36499pF  1.26587pF  1.45240pF
|C_comp_pulldown   963.69029fF  1.01008pF  944.70272fF
Vinl = 450.0mV
Vinh = 660.0mV
Vmeas = 600.0mV   | Reference voltage for timing measurements
Cref  = 50.0pF   | Timing specification test load capacitance value
Rref  = 1.0MOhm   | Timing specification test load resistance value
Vref  = 660.0mV   | Timing specification test load voltage
[Model Spec]
| TIME_THRESHOLD on pin ZIV11 is "CMOS" :
| Rising=50.0% of vdd   Falling=50.0% of vdd
Vinl 441.50000mV 335.50000mV 487.50000mV
Vinh 755.50000mV 552.50000mV 839.50000mV
| variable   typ   min   max
[Temperature Range] 25.0 140.0 -40.0
| variable   typ   min   max
[Voltage Range] 1.2V 900.0mV 1.32V
| variable   typ   min   max
[POWER Clamp Reference] 1.2V 900.0mV 1.32V
| variable   typ   min   max
[GND Clamp Reference] 0V 0V 0V
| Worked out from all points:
|   slope of the pulldown table from 0 to 0.18 V, typ, clamps not added: 522 ohm
|   slope of the pullup table from 0 to 0.18 V, typ, clamps not added: 1.49 kohm
|   GND clamp passes 1 mA (typ) near -0.54 V on its own axis
|   POWER clamp passes 1 mA (typ) near -0.83 V on its own axis
[POWER Clamp]
-1.2V     116.7mA    92.13mA    136.9mA
-1.09V    69.42mA    68.21mA    67.14mA
-1.02V    41.75mA    52.99mA    28.91mA
-990mV    30.98mA    46.47mA    16.09mA
-970mV    24.36mA    42.12mA    9.575mA
-940mV    15.59mA    35.6mA     3.485mA
-910mV    8.693mA    29.07mA    1.01mA
-860mV    2.259mA    18.59mA    104.6uA
-780mV    143.1uA    6.246mA    2.554uA
-720mV    16.22uA    1.846mA    157.1nA
-650mV    1.266uA    330.3uA    6.104nA
2.4V      0A         0A         0A
[GND Clamp]
-1.2V     -535.9mA   -765.1mA   -422.7mA
-990mV    -178.9mA   -408.1mA   -65.72mA
-970mV    -144.9mA   -374.1mA   -40.58mA
-920mV    -59.91mA   -289.1mA   -18.78mA
-900mV    -37.04mA   -255.1mA   -15.98mA
-880mV    -24.11mA   -221.1mA   -14.15mA
-780mV    -7.189mA   -55.54mA   -8.417mA
-750mV    -5.884mA   -29.71mA   -7.031mA
-700mV    -4.228mA   -11.41mA   -4.967mA
-610mV    -2.056mA   -3.105mA   -2.146mA
-390mV    -47.28uA   -188.8uA   -17.26uA
2.4V      740.6pA    197.9nA    245.1pA
| variable   typ   min   max
[Pullup Reference] 1.2V 900.0mV 1.32V
| variable   typ   min   max
[Pulldown Reference] 0V 0V 0V
[Pullup]
-1.2V     586.5uA    218uA      941.8uA
-560mV    586.5uA    218uA      939.3uA
-530mV    586.5uA    218uA      896.2uA
-490mV    573uA      218uA      805.2uA
-370mV    392.1uA    215.1uA    543.5uA
-240mV    230uA      123.4uA    331.1uA
-80mV     68.07uA    32.58uA    101.5uA
170mV     -115.1uA   -47.4uA    -178.3uA
420mV     -215.5uA   -74.74uA   -346.1uA
540mV     -237.3uA   -77.13uA   -389.8uA
790mV     -251.9uA   -78.78uA   -426uA
2.4V      -265.6uA   -81.56uA   -454.9uA
[Pulldown]
-1.2V     -1.691mA   -654.5uA   -2.583mA
-750mV    -1.69mA    -654.5uA   -2.563mA
-540mV    -1.526mA   -648.1uA   -2.381mA
-420mV    -1.264mA   -558.3uA   -1.971mA
-80mV     -206.7uA   -79.1uA    -354.6uA
80mV      176uA      59.82uA    314uA
290mV     478.8uA    141.1uA    868.7uA
420mV     565.7uA    150.4uA    1.047mA
1.54V     603uA      226.8uA    1.14mA
1.72V     729uA      226.8uA    1.15mA
2.01V     836.2uA    226.8uA    1.564mA
2.4V      836.2uA    226.8uA    1.572mA
[Ramp]
dV/dt_r 7.74199mV/11.17719ns 2.37132mV/29.62579ns 13.24821mV/6.42853ns
dV/dt_f 17.94414mV/11.62365ns 4.53446mV/29.75439ns 34.19534mV/7.10998ns
R_load = 50.0
| Removed startup time: 0s 0s 0s  .
| Removed end time: 49.25ns.
[Rising Waveform]
R_fixture   = 50.0
V_fixture   = 1.2V
V_fixture_min = 900.0mV
V_fixture_max = 1.32V
0s        1.17V      892.4mV    1.263V
3.85ns    1.17V      892.4mV    1.263V
5ns       1.17V      892.4mV    1.299V
5.45ns    1.17V      892.4mV    1.31V
6.15ns    1.175V     892.4mV    1.317V
7ns       1.185V     892.4mV    1.319V
8.05ns    1.194V     892.4mV    1.319V
11.05ns   1.199V     892.4mV    1.32V
21.15ns   1.2V       899.3mV    1.32V
49.25ns   1.2V       899.9mV    1.32V
| Removed startup time: 0s 0s 0s  .
| Removed end time: 199.25ns.
[Falling Waveform]
R_fixture   = 50.0
V_fixture   = 1.2V
V_fixture_min = 900.0mV
V_fixture_max = 1.32V
0s        1.2V       900mV      1.32V
13.95ns   1.2V       900mV      1.32V
17.8ns    1.2V       900mV      1.293V
21.85ns   1.2V       900mV      1.276V
25.45ns   1.193V     900mV      1.269V
32.55ns   1.18V      900mV      1.264V
40.65ns   1.173V     900mV      1.263V
56.95ns   1.17V      899.9mV    1.263V
101.7ns   1.17V      893.3mV    1.263V
199.3ns   1.17V      892.4mV    1.263V
| Removed startup time: 0s 0s 0s  .
| Removed end time: 199.25ns.
[Rising Waveform]
R_fixture   = 50.0
V_fixture   = 0V
V_fixture_min = 0V
V_fixture_max = 0V
0s        10.49nV    318.6nV    9.881nV
9.8ns     -292.9uV   2.546uV    29.82uV
15.5ns    -17.51uV   -85.2uV    13.42mV
18.65ns   1.651mV    -75.63uV   18.22mV
21.9ns    4.412mV    -88.42uV   20.55mV
28.45ns   9.155mV    -44.52uV   21.82mV
36.6ns    11.83mV    -6.807uV   22.04mV
48.8ns    12.74mV    232.9uV    22.07mV
97.6ns    12.9mV     3.576mV    22.08mV
199.3ns   12.9mV     3.953mV    22.08mV
| Removed startup time: 0s 0s 0s  .
| Removed end time: 69.2ns.
[Falling Waveform]
R_fixture   = 50.0
V_fixture   = 0V
V_fixture_min = 0V
V_fixture_max = 0V
0s        12.91mV    3.962mV    22.08mV
3.95ns    12.9mV     3.962mV    22.11mV
5.95ns    12.87mV    3.961mV    15.52mV
9.8ns     8.01mV     3.964mV    5.097mV
11.8ns    5.815mV    3.962mV    1.824mV
14.35ns   3.45mV     3.515mV    438.3uV
18.35ns   914.8uV    2.833mV    168.9uV
22.6ns    237.8uV    2.171mV    75.75uV
41ns      22.32uV    293.5uV    1.419uV
69.2ns    475.4nV    29.48uV    7.153nV
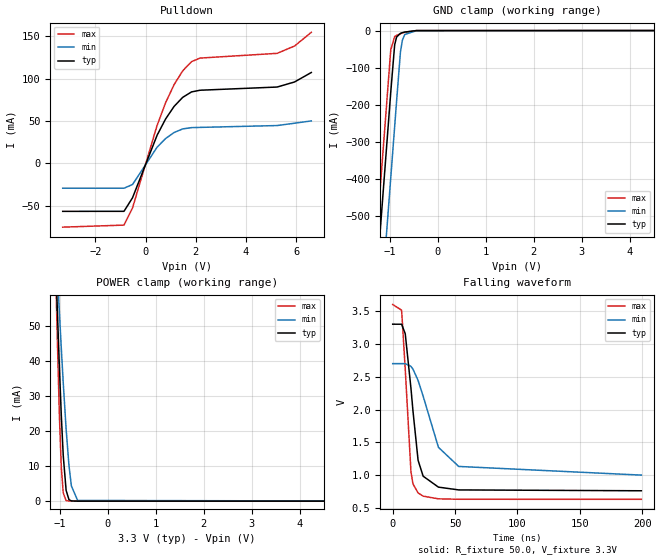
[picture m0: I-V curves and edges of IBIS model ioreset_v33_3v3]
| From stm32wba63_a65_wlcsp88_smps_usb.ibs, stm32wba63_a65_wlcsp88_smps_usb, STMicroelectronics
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[Model]   ioreset_v33_3v3
Model_type I/O_open_drain
Polarity   Inverting
Enable   Active-Low
| CAP_THRESHOLD on pad IOFT is "UDTCAPC" :
| Rising=30.0% of vddiom   Falling=70.0% of vddiom
| C_comp min and max val. don't necessarily correlate with the min and max pvt
| but are the smallest and greatest pad capacitance found.
| var   typ   min   max
C_comp   2.65369pF  2.57860pF  2.68550pF
|C_comp_pulldown   2.65369pF  2.57860pF  2.68550pF
Vinl = 1.35V
Vinh = 1.8V
Vmeas = 1.65V   | Reference voltage for timing measurements
Cref  = 50.0pF   | Timing specification test load capacitance value
Rref  = 1.0MOhm   | Timing specification test load resistance value
Vref  = 1.815V   | Timing specification test load voltage
[Model Spec]
| TIME_THRESHOLD on pin ZIV33M is "CMOS" :
| Rising=50.0% of vddiom   Falling=50.0% of vddiom
Vinl 1.28550V 1.07650V 1.37150V
Vinh 1.78850V 1.51150V 1.89250V
| variable   typ   min   max
[Temperature Range] 25.0 140.0 -40.0
| variable   typ   min   max
[Voltage Range] 3.3V 2.7V 3.6V
| variable   typ   min   max
[POWER Clamp Reference] 3.3V 2.7V 3.6V
| variable   typ   min   max
[GND Clamp Reference] 0V 0V 0V
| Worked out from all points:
|   slope of the pulldown table from 0 to 0.495 V, typ, clamps not added: 14 ohm
|   GND clamp passes 1 mA (typ) near -0.54 V on its own axis
|   POWER clamp passes 1 mA (typ) near -0.83 V on its own axis
|   falling waveform, R_fixture 50.0, V_fixture 3.3V: 20-80 % time 7.7ns typ, 17.5ns min, 5.02ns max; typ from 3.3 V to 0.765 V
[POWER Clamp]
-3.3V     1.123A     753mA      1.645A
-1.09V    69.42mA    75.17mA    67.14mA
-1.08V    65.31mA    72.42mA    61.23mA
-1.06V    57.23mA    66.98mA    49.77mA
-1.01V    38.06mA    53.68mA    24.29mA
-970mV    24.36mA    43.46mA    9.575mA
-930mV    13.06mA    33.74mA    2.352mA
-870mV    3.065mA    20.56mA    165.9uA
-810mV    418.4uA    10.06mA    10.3uA
-760mV    69.41uA    4.321mA    1.008uA
-630mV    611.2nA    197.1uA    2.638nA
6.6V      0A         0A         0A
[GND Clamp]
-3.3V     -4.107A    -4.338A    -3.993A
-1.33V    -758.5mA   -989.4mA   -644.1mA
-1.25V    -622.5mA   -853.4mA   -508.1mA
-990mV    -180.5mA   -411.4mA   -66.08mA
-980mV    -163.5mA   -394.4mA   -51.4mA
-900mV    -38.36mA   -258.4mA   -16.27mA
-860mV    -17.65mA   -190.4mA   -13.01mA
-780mV    -7.648mA   -58.45mA   -8.62mA
-740mV    -5.858mA   -26.35mA   -6.755mA
-690mV    -4.169mA   -10.77mA   -4.704mA
-450mV    -218.5uA   -526.6uA   -128uA
6.6V      694.1pA    42.51nA    528.7pA
| variable   typ   min   max
[Pullup Reference] 3.3V 2.7V 3.6V
| variable   typ   min   max
[Pulldown Reference] 0V 0V 0V
[Pulldown]
-3.3V     -56.68mA   -29.4mA    -75.34mA
-860mV    -56.65mA   -29.4mA    -72.92mA
-520mV    -40.67mA   -25mA      -52.61mA
460mV     33.22mA    19.07mA    44.88mA
800mV     52.49mA    29.33mA    71.69mA
1.14V     67.34mA    36.45mA    93.11mA
1.48V     77.88mA    40.62mA    109.2mA
1.83V     84.28mA    42.12mA    120mA
2.17V     86.26mA    42.39mA    124.2mA
5.24V     90.04mA    44.58mA    129.8mA
5.93V     95.99mA    47.33mA    138.4mA
6.6V      107.2mA    50.05mA    154.6mA
[Ramp]
dV/dt_r 1.53331V/219.4909ps 1.02616V/330.75878ps 1.78662V/192.14824ps
dV/dt_f 1.52116V/7.6556ns 1.01831V/17.21785ns 1.77915V/4.95025ns
R_load = 50.0
| Removed startup time: 0s 0s 0s  .
| Removed end time: 99.99us.
|[Rising Waveform]
|R_fixture   = 50.0
|V_fixture   = 3.3V
|V_fixture_min = 2.7V
|V_fixture_max = 3.6V
|  0s  764.74058mV  1.00268V  634.36314mV
|  2.04us  764.74058mV  1.00268V  634.36314mV
|  4.08us  764.74058mV  1.00268V  634.36314mV
|  6.12us  764.74058mV  1.00268V  634.36314mV
|  8.16us  764.74058mV  1.00268V  634.36314mV
|  10.2us  764.74058mV  1.00268V  634.36314mV
|  12.24us  764.74058mV  1.00268V  634.36314mV
|  14.29us  764.74058mV  1.00268V  634.36314mV
|  16.33us  764.74058mV  1.00268V  634.36314mV
|  18.37us  764.74058mV  1.00268V  634.36314mV
|  20.41us  764.74058mV  1.00268V  634.36314mV
|  22.45us  764.74058mV  1.00268V  634.36314mV
|  22.72us  764.74058mV  1.00268V  634.36314mV
|  22.73us  764.74058mV  1.00268V  3.58654V
|  22.74us  764.74058mV  1.00268V  3.59995V
|  22.75us  764.74058mV  1.00268V  3.59998V
|  22.76us  764.74058mV  1.00268V  3.59998V
|  22.77us  764.74058mV  1.00268V  3.59999V
|  22.81us  764.74058mV  1.00268V  3.59999V
|  22.82us  764.74058mV  1.00268V  3.60000V
|  24.49us  764.74058mV  1.00268V  3.60000V
|  25.01us  764.74058mV  1.00268V  3.60000V
|  25.02us  764.74058mV  1.00268V  3.60000V
|  26.53us  764.74058mV  1.00268V  3.60000V
|  28.57us  764.74058mV  1.00268V  3.60000V
|  30.61us  764.74058mV  1.00268V  3.60000V
|  32.44us  764.74058mV  1.00268V  3.60000V
|  32.45us  764.74064mV  1.00268V  3.60000V
|  32.46us  3.29985V  1.00268V  3.60000V
|  32.47us  3.29996V  1.00268V  3.60000V
|  32.48us  3.29998V  1.00268V  3.60000V
|  32.49us  3.29998V  1.00268V  3.60000V
|  32.5us  3.29999V  1.00268V  3.60000V
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[Falling Waveform]
R_fixture   = 50.0
V_fixture   = 3.3V
V_fixture_min = 2.7V
V_fixture_max = 3.6V
0s        3.3V       2.7V       3.6V
7.15ns    3.3V       2.7V       3.513V
10.05ns   3.155V     2.7V       2.614V
14.65ns   2.321V     2.658V     1.049V
16.25ns   1.979V     2.616V     869.2mV
20.35ns   1.228V     2.444V     731.2mV
24.4ns    986.6mV    2.205V     682.7mV
36.65ns   820mV      1.426V     642.1mV
52.9ns    777.7mV    1.135V     635.5mV
199.3ns   764.7mV    1.003V     634.4mV
